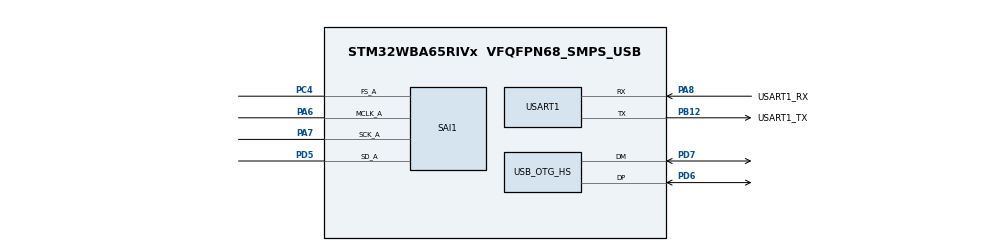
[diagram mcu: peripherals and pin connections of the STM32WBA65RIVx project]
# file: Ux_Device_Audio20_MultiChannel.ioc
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CORTEX_M33_NS.userName=CORTEX_M33
Mcu.Family=STM32WBA
Mcu.Name=STM32WBA65RIVx
Mcu.Package=VFQFPN68_SMPS_USB
NVIC.PriorityGroup=NVIC_PRIORITYGROUP_4
NVIC.TIM17_IRQn=true\:15\:0\:false\:false\:true\:false\:false\:true\:true
NVIC.TimeBase=TIM17_IRQn
NVIC.TimeBaseIP=TIM17
NVIC.USB_OTG_HS_IRQn=true\:6\:0\:true\:false\:true\:false\:true\:true\:true
OSC_IN.Mode=HSE-External-Oscillator
OSC_IN.Signal=RCC_OSC_IN
OSC_OUT.Mode=HSE-External-Oscillator
OSC_OUT.Signal=RCC_OSC_OUT
PA6.Mode=SAI_A_MasterWithClock
PA6.Signal=SAI1_MCLK_A
PA7.Mode=SAI_A_MasterWithClock
PA7.Signal=SAI1_SCK_A
PA8.GPIO_Label=USART1_RX
PA8.GPIO_Speed=GPIO_SPEED_FREQ_HIGH
PA8.Mode=Asynchronous
PA8.Signal=USART1_RX
PB12.GPIO_Label=USART1_TX
PB12.GPIO_Speed=GPIO_SPEED_FREQ_HIGH
PB12.Mode=Asynchronous
PB12.Signal=USART1_TX
PC4.Mode=SAI_A_MasterWithClock
PC4.Signal=SAI1_FS_A
PD5.Mode=SAI_A_MasterWithClock
PD5.Signal=SAI1_SD_A
PD6.Mode=Internal_Phy_Device
PD6.Signal=USB_OTG_HS_DP
PD7.Mode=Internal_Phy_Device
PD7.Signal=USB_OTG_HS_DM
ProjectManager.HeapSize=0x200
ProjectManager.StackSize=0x400
ProjectManager.TargetToolchain=EWARM V9.60
RCC.ADCFreq_Value=100000000
RCC.AHB5CLKDivider=DIV4
RCC.AHBFreq_Value=100000000
RCC.APB1Freq_Value=100000000
RCC.APB1TimFreq_Value=100000000
RCC.APB2Freq_Value=100000000
RCC.APB2TimFreq_Value=100000000
RCC.CortexCLockSelectionVirtual=RCC_SYSTICKCLKSOURCE_LSE
RCC.CortexFreq_Value=32768
RCC.FLatency=FLASH_LATENCY_3
RCC.HCLKFreq_Value=100000000
RCC.HSE_VALUE=32000000
RCC.HSI_VALUE=16000000
RCC.I2C1CLockSelection=RCC_I2C1CLKSOURCE_HSI
RCC.I2C2CLockSelection=RCC_I2C2CLKSOURCE_HSI
RCC.I2C3CLockSelection=RCC_I2C3CLKSOURCE_HSI
RCC.I2C4CLockSelection=RCC_I2C4CLKSOURCE_HSI
RCC.LPUART1CLockSelectionVirtual=RCC_LPUART1CLKSOURCE_HSI
RCC.LSE_VALUE=32768
RCC.LSI1_VALUE=32000
RCC.LSI2_VALUE=32000
RCC.PLLFRACN=4096
RCC.PLLM=2
RCC.PLLN=12
RCC.PLLSourceVirtual=RCC_PLLSOURCE_HSE
RCC.PWR_Regulator_Voltage_Scale=PWR_REGULATOR_VOLTAGE_SCALE1
RCC.RSTClockSelectionVirtual=RCC_RADIOSTCLKSOURCE_LSE
RCC.RTCClockSelection=RCC_RTCCLKSOURCE_LSE
RCC.SPI1CLockSelection=RCC_SPI1CLKSOURCE_HSI
RCC.SPI3CLockSelection=RCC_SPI3CLKSOURCE_HSI
RCC.SYSCLKFreq_VALUE=100000000
RCC.SYSCLKSourceVirtual=RCC_SYSCLKSOURCE_PLLCLK
RCC.SupplySource=PWR_LDO_SUPPLY
RCC.USART2CLockSelectionVirtual=RCC_USART2CLKSOURCE_HSI
RCC.USART3CLockSelection=RCC_USART3CLKSOURCE_HSI
RCC.VCOOutputFreq_Value=200000000
SAI1.ErrorAudioFreq-SAI_A_MasterWithClock=-67.44 %
SAI1.Instance-SAI_A_MasterWithClock=SAI$Index_Block_A
SAI1.MckOutput=SAI_MCK_OUTPUT_ENABLE
SAI1.RealAudioFreq-SAI_A_MasterWithClock=62.5 KHz
SAI1.VirtualMode-SAI_A_MasterWithClock=VM_MASTER
THREADX.TX_APP_GENERATE_INIT_CODE=false
USART1.VirtualMode-Asynchronous=VM_ASYNC
USBX.BSP.number=1
USBX.Core_System=1
USBX.MAX_POWER_IN_MILLI_AMPER=25
USBX.USBD_ADUIO_EPIN_FEEDBACK_HS_BINTERVAL=4
USBX.USBD_AUDIO_EPIN_ADDR=2
USBX.USBD_AUDIO_EPIN_FS_MPS=392
USBX.USBD_AUDIO_EPIN_HS_BINTERVAL=4
USBX.USBD_AUDIO_EPIN_HS_MPS=392
USBX.USBD_AUDIO_EPOUT_HS_BINTERVAL=4
USBX.USBD_AUDIO_PLAY_CHANNEL_COUNT=4
USBX.USBD_AUDIO_PLAY_CHANNEL_MAP=0x33
USBX.USBD_AUDIO_PLAY_EPOUT_FS_MPS=392
USBX.USBD_AUDIO_PLAY_EPOUT_HS_MPS=392
USBX.USBD_AUDIO_RECORD_CHANNEL_COUNT=4
USBX.USBD_AUDIO_RECORD_CHANNEL_MAP=0x33
USBX.USBD_FRAMEWORK_MAX_DESC_SZ=500
USBX.USBD_PID=0x5730
USBX.USBD_PRODUCT_STRING=STM32 AUDIO20 STREAMING
USBX.USBD_SERIAL_NUMBER=AUDIO002
USBX.USBD_VID=0x0483
USBX.USBX_DEVICE_APP_THREAD_PRIO=20
USBX.USBX_SYS_SIZE=20 * 1024
USBX.UX_ALIGN_MIN=UX_ALIGN_32
USBX.UX_APP_MEM_POOL_SIZE=53 * 1024
USBX.UX_DEVICE_AUDIO_CORE=1
USBX.UX_DEVICE_AUDIO_PLAYBACK=1
USBX.UX_DEVICE_AUDIO_RECORDING=1
USBX.UX_DEVICE_CLASS_AUDIO_FEEDBACK_SUPPORT=1
USBX.UX_DEVICE_ENDPOINT_BUFFER_OWNER=1
USBX.UX_Device_Controller=1
USBX.UX_Device_CoreStack=1
USBX.UX_OTG_SUPPORT=1
USBX.UX_SLAVE_REQUEST_CONTROL_MAX_LENGTH=512
USBX.UX_SLAVE_REQUEST_DATA_MAX_LENGTH=64
USBX0.BSP.STBoard=false
USBX0.BSP.api=Unknown
USBX0.BSP.instance=USB_OTG_HS
USBX0.BSP.ip=USB_OTG_HS
USBX0.BSP.mode=Device_Only
USBX0.BSP.name=USB_Device
USBX0.BSP.solution=USB_OTG_HS
USB_OTG_HS.RefClockSelection=SYSCFG_OTG_HS_PHY_CLK_SELECT_6
USB_OTG_HS.Sof_enable=ENABLE
USB_OTG_HS.VirtualMode=Device_HS
VP_CORTEX_M33_NS_VS_Hclk.Mode=Hclk_Mode
VP_ICACHE_VS_ICACHE.Mode=DirectMappedCache
VP_MEMORYMAP_VS_MEMORYMAP.Mode=CurAppReg
VP_PWR_VS_SECSignals.Mode=Security/Privilege
VP_SYS_VS_tim17.Mode=TIM17
VP_THREADX_VS_RTOSJjThreadXJjCoreJjDefault.Mode=Core_Default
VP_USBX_Core_System.Mode=Core_System
VP_USBX_UX\ Device\ AUDIO_HS.Mode=UX_Device_class_AUDIO_HS
VP_USBX_UX\ Device\ AUDIO_PlAYBACK_HS.Mode=UX_Device_class_AUDIO_PLAYBACK_HS
VP_USBX_UX\ Device\ AUDIO_RECORDING_HS.Mode=UX_Device_class_AUDIO_RECORDING_HS
VP_USBX_UX\ Device\ Controller_HS.Mode=UX_Device_Controller_HS
VP_USBX_UX\ Device\ CoreStack_HS.Mode=UX_Device_CoreStack_HS
board=STM32WBA65I-DK1

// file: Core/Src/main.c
/* USER CODE BEGIN Header */
/**
  ******************************************************************************
  * @file           : main.c
  * @brief          : Main program body
  ******************************************************************************
  * @attention
  *
  * Copyright (c) 2026 STMicroelectronics.
  * All rights reserved.
  *
  * This software is licensed under terms that can be found in the LICENSE file
  * in the root directory of this software component.
  * If no LICENSE file comes with this software, it is provided AS-IS.
  *
  ******************************************************************************
  */
/* USER CODE END Header */
#include "app_threadx.h"
#include "main.h"

/* USER CODE BEGIN Includes */
#if defined(__ICCARM__)
#include <LowLevelIOInterface.h>
#endif /* __ICCARM__ */
#include <stdio.h>
#include <string.h>
/* USER CODE END Includes */

/* USER CODE BEGIN PD */
#if defined(__ICCARM__)
/* New definition from EWARM V9, compatible with EWARM8 */
int iar_fputc(int ch);
#define PUTCHAR_PROTOTYPE int iar_fputc(int ch)
#elif defined(__ARMCC_VERSION)
/* ARM Compiler 6*/
#define PUTCHAR_PROTOTYPE int fputc(int ch, FILE *f)
#elif defined(__GNUC__)
#define PUTCHAR_PROTOTYPE int __io_putchar(int ch)
#endif /* __ICCARM__ */
/* USER CODE END PD */

UART_HandleTypeDef huart1;

PCD_HandleTypeDef hpcd_USB_OTG_HS;

void SystemClock_Config(void);
static void MX_GPIO_Init(void);
static void MX_ICACHE_Init(void);
static void MX_USART1_UART_Init(void);

int main(void)
{

  /* MCU Configuration--------------------------------------------------------*/

  /* Reset of all peripherals, Initializes the Flash interface and the Systick. */
  HAL_Init();

  /* Configure the system clock */
  SystemClock_Config();

  /* Initialize all configured peripherals */
  MX_GPIO_Init();
  MX_ICACHE_Init();
  MX_USART1_UART_Init();

  MX_ThreadX_Init();

  /* We should never get here as control is now taken by the scheduler */

  /* Infinite loop */
  while (1)
  {

  }
}

void SystemClock_Config(void)
{
  RCC_OscInitTypeDef RCC_OscInitStruct = {0};
  RCC_ClkInitTypeDef RCC_ClkInitStruct = {0};

  /** Supply configuration update enable
  */
  HAL_PWREx_ConfigSupply(PWR_LDO_SUPPLY);

  /** Configure the main internal regulator output voltage
  */
  if (HAL_PWREx_ControlVoltageScaling(PWR_REGULATOR_VOLTAGE_SCALE1) != HAL_OK)
  {
    Error_Handler();
  }

  /** Initializes the CPU, AHB and APB busses clocks
  */
  RCC_OscInitStruct.OscillatorType = RCC_OSCILLATORTYPE_HSI|RCC_OSCILLATORTYPE_HSE
                              |RCC_OSCILLATORTYPE_LSE;
  RCC_OscInitStruct.HSEState = RCC_HSE_ON;
  RCC_OscInitStruct.HSEDiv = RCC_HSE_DIV1;
  RCC_OscInitStruct.LSEState = RCC_LSE_OFF;
  RCC_OscInitStruct.HSIState = RCC_HSI_ON;
  RCC_OscInitStruct.HSICalibrationValue = RCC_HSICALIBRATION_DEFAULT;
  RCC_OscInitStruct.PLL1.PLLState = RCC_PLL_ON;
  RCC_OscInitStruct.PLL1.PLLSource = RCC_PLLSOURCE_HSE;
  RCC_OscInitStruct.PLL1.PLLM = 2;
  RCC_OscInitStruct.PLL1.PLLN = 12;
  RCC_OscInitStruct.PLL1.PLLP = 2;
  RCC_OscInitStruct.PLL1.PLLQ = 2;
  RCC_OscInitStruct.PLL1.PLLR = 2;
  RCC_OscInitStruct.PLL1.PLLFractional = 4096;
  if (HAL_RCC_OscConfig(&RCC_OscInitStruct) != HAL_OK)
  {
    Error_Handler();
  }

  /** Initializes the CPU, AHB and APB busses clocks
  */
  RCC_ClkInitStruct.ClockType = RCC_CLOCKTYPE_HCLK|RCC_CLOCKTYPE_SYSCLK
                              |RCC_CLOCKTYPE_PCLK1|RCC_CLOCKTYPE_PCLK2
                              |RCC_CLOCKTYPE_PCLK7|RCC_CLOCKTYPE_HCLK5;
  RCC_ClkInitStruct.SYSCLKSource = RCC_SYSCLKSOURCE_PLLCLK;
  RCC_ClkInitStruct.AHBCLKDivider = RCC_SYSCLK_DIV1;
  RCC_ClkInitStruct.APB1CLKDivider = RCC_HCLK_DIV1;
  RCC_ClkInitStruct.APB2CLKDivider = RCC_HCLK_DIV1;
  RCC_ClkInitStruct.APB7CLKDivider = RCC_HCLK_DIV1;
  RCC_ClkInitStruct.AHB5_PLL1_CLKDivider = RCC_SYSCLK_PLL1_DIV4;
  RCC_ClkInitStruct.AHB5_HSEHSI_CLKDivider = RCC_SYSCLK_HSEHSI_DIV1;

  if (HAL_RCC_ClockConfig(&RCC_ClkInitStruct, FLASH_LATENCY_3) != HAL_OK)
  {
    Error_Handler();
  }
}

static void MX_ICACHE_Init(void)
{

  /** Enable instruction cache in 1-way (direct mapped cache)
  */
  if (HAL_ICACHE_ConfigAssociativityMode(ICACHE_1WAY) != HAL_OK)
  {
    Error_Handler();
  }
  if (HAL_ICACHE_Enable() != HAL_OK)
  {
    Error_Handler();
  }

}

static void MX_USART1_UART_Init(void)
{

  huart1.Instance = USART1;
  huart1.Init.BaudRate = 115200;
  huart1.Init.WordLength = UART_WORDLENGTH_8B;
  huart1.Init.StopBits = UART_STOPBITS_1;
  huart1.Init.Parity = UART_PARITY_NONE;
  huart1.Init.Mode = UART_MODE_TX_RX;
  huart1.Init.HwFlowCtl = UART_HWCONTROL_NONE;
  huart1.Init.OverSampling = UART_OVERSAMPLING_16;
  huart1.Init.OneBitSampling = UART_ONE_BIT_SAMPLE_DISABLE;
  huart1.Init.ClockPrescaler = UART_PRESCALER_DIV1;
  huart1.AdvancedInit.AdvFeatureInit = UART_ADVFEATURE_NO_INIT;
  if (HAL_UART_Init(&huart1) != HAL_OK)
  {
    Error_Handler();
  }
  if (HAL_UARTEx_SetTxFifoThreshold(&huart1, UART_TXFIFO_THRESHOLD_1_8) != HAL_OK)
  {
    Error_Handler();
  }
  if (HAL_UARTEx_SetRxFifoThreshold(&huart1, UART_RXFIFO_THRESHOLD_1_8) != HAL_OK)
  {
    Error_Handler();
  }
  if (HAL_UARTEx_DisableFifoMode(&huart1) != HAL_OK)
  {
    Error_Handler();
  }

}

void MX_USB_OTG_HS_PCD_Init(void)
{

  /* USER CODE BEGIN USB_OTG_HS_PCD_Init 1 */
  memset(&hpcd_USB_OTG_HS, 0x0, sizeof(PCD_HandleTypeDef));
  /* USER CODE END USB_OTG_HS_PCD_Init 1 */
  hpcd_USB_OTG_HS.Instance = USB_OTG_HS;
  hpcd_USB_OTG_HS.Init.dev_endpoints = 9;
  hpcd_USB_OTG_HS.Init.speed = PCD_SPEED_HIGH;
  hpcd_USB_OTG_HS.Init.phy_itface = USB_OTG_HS_EMBEDDED_PHY;
  hpcd_USB_OTG_HS.Init.Sof_enable = ENABLE;
  hpcd_USB_OTG_HS.Init.low_power_enable = DISABLE;
  hpcd_USB_OTG_HS.Init.lpm_enable = DISABLE;
  hpcd_USB_OTG_HS.Init.use_dedicated_ep1 = DISABLE;
  hpcd_USB_OTG_HS.Init.vbus_sensing_enable = DISABLE;
  hpcd_USB_OTG_HS.Init.dma_enable = DISABLE;
  if (HAL_PCD_Init(&hpcd_USB_OTG_HS) != HAL_OK)
  {
    Error_Handler();
  }
  /* USER CODE BEGIN USB_OTG_HS_PCD_Init 2 */

  /* Set Rx FIFO */
  HAL_PCDEx_SetRxFiFo(&hpcd_USB_OTG_HS, 0x200);

  /* Set Tx FIFO 0 */
  HAL_PCDEx_SetTxFiFo(&hpcd_USB_OTG_HS, 0, USBD_MAX_EP0_SIZE/4);

#ifdef UX_DEVICE_CLASS_AUDIO_FEEDBACK_SUPPORT
  /* Set Tx FIFO 1 */
  HAL_PCDEx_SetTxFiFo(&hpcd_USB_OTG_HS, 1, USBD_AUDIO_PLAY_EP_FEEDBACK_HS_MPS/4);
#endif

  /* Set Tx FIFO 2 */
  HAL_PCDEx_SetTxFiFo(&hpcd_USB_OTG_HS, 2, USBD_AUDIO_RECORD_EPIN_HS_MPS/4);

  /* USER CODE END USB_OTG_HS_PCD_Init 2 */

}

static void MX_GPIO_Init(void)
{

  /* GPIO Ports Clock Enable */
  __HAL_RCC_GPIOB_CLK_ENABLE();
  __HAL_RCC_GPIOA_CLK_ENABLE();
  __HAL_RCC_GPIOD_CLK_ENABLE();
  __HAL_RCC_GPIOC_CLK_ENABLE();

}

/* USER CODE BEGIN 4 */
/**
  * @brief  Retargets the C library __write function to the IAR function iar_fputc.
  * @param  file: file descriptor.
  * @param  ptr: pointer to the buffer where the data is stored.
  * @param  len: length of the data to write in bytes.
  * @retval length of the written data in bytes.
  */
#if defined(__ICCARM__)
size_t __write(int file, unsigned char const *ptr, size_t len)
{
  size_t idx;
  unsigned char const *pdata = ptr;

  for (idx = 0; idx < len; idx++)
  {
    iar_fputc((int)*pdata);
    pdata++;
  }
  return len;
}
#endif /* __ICCARM__ */

/**
  * @brief  Retargets the C library printf function to the USART.
  * @param  None
  * @retval None
  */
PUTCHAR_PROTOTYPE
{
  /* Place your implementation of fputc here */
  /* e.g. write a character to the USART1 and Loop until the end of transmission */
  HAL_UART_Transmit(&huart1, (uint8_t *)&ch, 1, 0xFFFF);
  return ch;
}
/* USER CODE END 4 */

void HAL_TIM_PeriodElapsedCallback(TIM_HandleTypeDef *htim)
{
  if (htim->Instance == TIM17)
  {
    HAL_IncTick();
  }
}

void Error_Handler(void)
{
  while (1)
  {
  }
}
